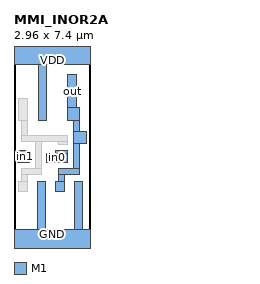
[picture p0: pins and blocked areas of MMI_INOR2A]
MACRO MMI_INOR2A
	CLASS CORE ;
	FOREIGN MMI_INOR2A 0 0 ;
	SIZE 2.96 BY 7.4 ;
	SYMMETRY X Y ;
	SITE CORE1 ;
	PIN out
		DIRECTION output ;
		USE SIGNAL ;
		PORT
			LAYER M1 ;
			RECT 2.09 5.225 2.43 6.505 ;
			LAYER M1 ;
			RECT 2.09 4.745 2.535 5.225 ;
			LAYER M1 ;
			RECT 2.305 4.295 2.535 4.745 ;
			LAYER M1 ;
			RECT 2.305 3.845 2.815 4.295 ;
			LAYER M1 ;
			RECT 2.305 2.875 2.535 3.845 ;
			LAYER M1 ;
			RECT 1.73 2.645 2.535 2.875 ;
			LAYER M1 ;
			RECT 1.73 2.345 1.96 2.645 ;
			LAYER M1 ;
			RECT 1.62 1.965 1.96 2.345 ;
		END
		AntennaDiffArea 1.1316 ;
	END out
	PIN in1
		DIRECTION input ;
		USE SIGNAL ;
		PORT
			LAYER M1 ;
			RECT 0.145 3.105 0.595 3.555 ;
		END
		AntennaGateArea 0.2484 ;
	END in1
	PIN GND
		DIRECTION inout ;
		USE GROUND ;
		PORT
			LAYER M1 ;
			RECT 0.9 0.5 1.24 2.345 ;
			LAYER M1 ;
			RECT 2.34 0.5 2.68 2.345 ;
			LAYER M1 ;
			RECT 0 -0.5 2.96 0.5 ;
		END
	END GND
	PIN VDD
		DIRECTION inout ;
		USE POWER ;
		PORT
			LAYER M1 ;
			RECT 0 6.9 2.96 7.9 ;
			LAYER M1 ;
			RECT 0.94 4.745 1.28 6.9 ;
		END
	END VDD
	PIN in0
		DIRECTION input ;
		USE SIGNAL ;
		PORT
			LAYER M1 ;
			RECT 1.625 3.445 2.075 3.555 ;
			LAYER M1 ;
			RECT 1.285 3.105 2.075 3.445 ;
		END
		AntennaGateArea 0.414 ;
	END in0
	OBS
		LAYER M1 ;
		RECT 0.18 4.745 0.52 5.585 ;
		LAYER M1 ;
		RECT 0.29 4.13 0.52 4.745 ;
		LAYER M1 ;
		RECT 0.29 3.9 2.07 4.13 ;
		LAYER M1 ;
		RECT 0.825 2.875 1.055 3.9 ;
		LAYER M1 ;
		RECT 1.73 3.79 2.07 3.9 ;
		LAYER M1 ;
		RECT 0.29 2.645 1.055 2.875 ;
		LAYER M1 ;
		RECT 0.29 2.345 0.52 2.645 ;
		LAYER M1 ;
		RECT 0.18 1.965 0.52 2.345 ;
	END
END MMI_INOR2A
